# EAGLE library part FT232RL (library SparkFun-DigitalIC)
USB UART FT232RL 4th Generation USB UART (USB <-> Serial) Controller. Spark Fun Electronics SKU : COM-00650 Production SKU IC-00870

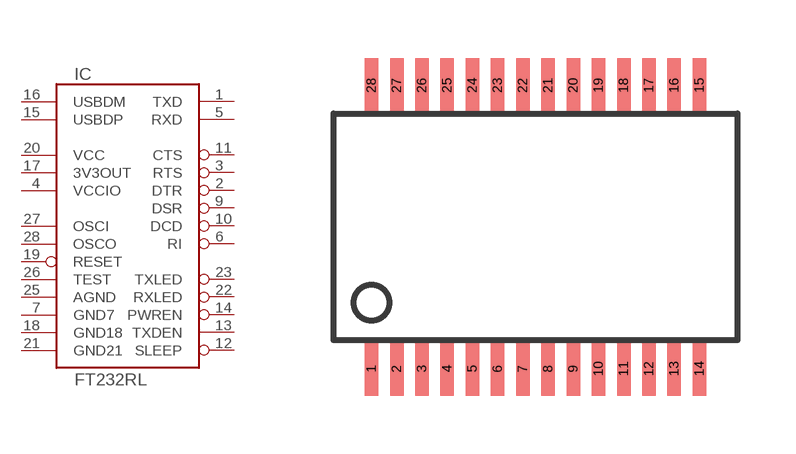
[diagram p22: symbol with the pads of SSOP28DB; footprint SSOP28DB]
Designator prefix IC

## FT232RLSSOP (PROD_ID: IC-00870)  [SSOP28DB]
1  TXD  out
2  DTR  out
3  RTS  out
4  VCCIO  pwr
5  RXD  in
6  RI  in
7  GND7  pwr
9  DSR  in
10  DCD  in
11  CTS  in
12  SLEEP  in
13  TXDEN  in
14  PWREN  in
15  USBDP
16  USBDM
17  3V3OUT  out
18  GND18  pwr
19  RESET  in
20  VCC  pwr
21  GND21  pwr
22  RXLED  in
23  TXLED  in
25  AGND  pwr
26  TEST  in
27  OSCI  in
28  OSCO  out

## Footprint SSOP28DB (pad centres in mm)
Small Shrink Outline Package
smd 0.348 x 1.397: 1 -4.225,-3.656; 2 -3.575,-3.656; 3 -2.925,-3.656; 4 -2.275,-3.656; 5 -1.625,-3.656; 6 -0.975,-3.656; 7 -0.325,-3.656; 8 0.325,-3.656; 9 0.975,-3.656; 10 1.625,-3.656; 11 2.275,-3.656; 12 2.925,-3.656; 13 3.575,-3.656; 14 4.225,-3.656; 15 4.225,3.656; 16 3.575,3.656; 17 2.925,3.656; 18 2.275,3.656; 19 1.625,3.656; 20 0.975,3.656; 21 0.325,3.656; 22 -0.325,3.656; 23 -0.975,3.656; 24 -1.625,3.656; 25 -2.275,3.656; 26 -2.925,3.656; 27 -3.575,3.656; 28 -4.225,3.656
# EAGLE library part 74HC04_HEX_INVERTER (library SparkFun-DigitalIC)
74HC04 Hex Inverter

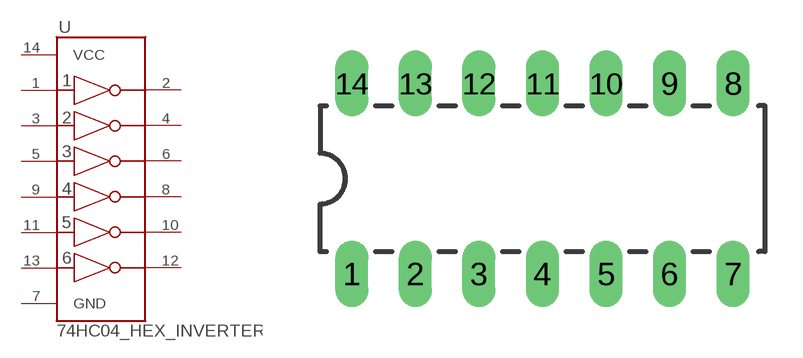
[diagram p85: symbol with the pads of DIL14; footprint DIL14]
Designator prefix U

## 74HC04_HEX_INVERTER  [DIL14]
1  1A  in
2  1Y  out
3  2A  in
4  2Y  out
5  3A  in
6  3Y  out
7  GND  pwr
8  4Y  out
9  4A  in
10  5Y  out
11  5A  in
12  6Y  out
13  6A  in
14  VCC  pwr

## Footprint DIL14 (pad centres in mm)
drill 0.813 long: 1 -8.89,-3.81; 2 -6.35,-3.81; 3 -3.81,-3.81; 4 -1.27,-3.81; 5 1.27,-3.81; 6 3.81,-3.81; 7 6.35,-3.81; 8 6.35,3.81; 9 3.81,3.81; 10 1.27,3.81; 11 -1.27,3.81; 12 -3.81,3.81; 13 -6.35,3.81; 14 -8.89,3.81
